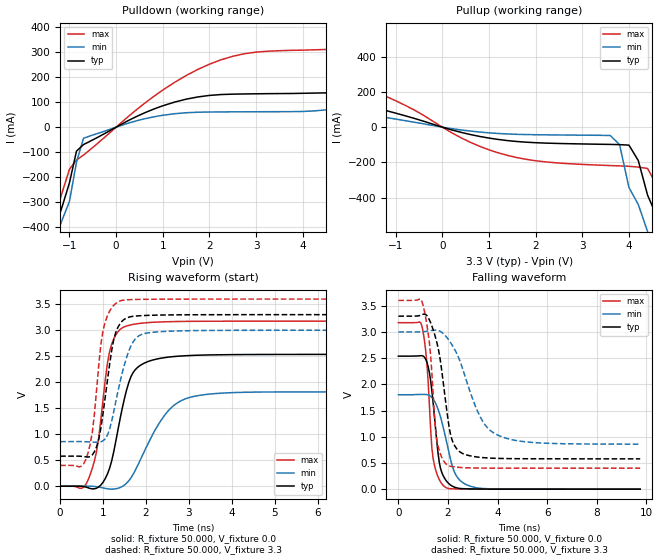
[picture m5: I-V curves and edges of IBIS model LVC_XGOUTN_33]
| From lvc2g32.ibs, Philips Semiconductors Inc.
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|   Model LVC_XGOUTN_33
[Model]   LVC_XGOUTN_33
Model_type   Output
Polarity   Non-Inverting
Vmeas =  1.5V
Cref  =  50.0pF
Rref  =  0.5k
Vref  =  0.0V
C_comp   3.30pF   2.07pF   4.36pF
[Model Spec]
| Note: The input and output voltage ratings may be exceeded if the input and
|   output current ratings are observed (please refer to the data sheet)
|   Subparameter   typ   min   max
| Timing Thresholds
Vmeas   1.5   1.5   1.5
|Ambient temperature:   25   85   -40
[Temperature Range]   35   95   -30
[Voltage Range]   3.3V   3.0V   3.6V
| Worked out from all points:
|   slope of the pulldown table from 0 to 0.495 V, typ, clamps not added: 10.4 ohm
|   slope of the pullup table from 0 to 0.495 V, typ, clamps not added: 14 ohm
|   rising waveform, R_fixture 50.000, V_fixture 0.0: 20-80 % time 409ps typ, 731ps min, 301ps max; typ from 0 V to 2.54 V
|   rising waveform, R_fixture 50.000, V_fixture 3.3: 20-80 % time 284ps typ, 377ps min, 243ps max; typ from 0.578 V to 3.3 V
|   falling waveform, R_fixture 50.000, V_fixture 0.0: 20-80 % time 340ps typ, 574ps min, 268ps max; typ from 2.54 V to 0 V
|   falling waveform, R_fixture 50.000, V_fixture 3.3: 20-80 % time 499ps typ, 1.04ns min, 318ps max; typ from 3.3 V to 0.578 V
|Process Range   nominal   slow   fast
[Pulldown]
| voltage   I(typ)   I(min)   I(max)
-5.5V     -4.541A    -4.577A    -4.501A
-1.45V    -533.3mA   -577.9mA   -483mA
-1.3V     -397.3mA   -442.4mA   -347.4mA
-1V       -221.8mA   -296.4mA   -168.2mA
-850mV    -95.82mA   -139.8mA   -131mA
-700mV    -69.66mA   -44.64mA   -111.7mA
1V        85.3mA     47.36mA    148.2mA
2.5V      131.8mA    61.07mA    283mA
5V        152.5mA    80.61mA    312.8mA
6V        202.1mA    110.9mA    399.6mA
9.25V     406.6mA    240.4mA    750.7mA
11V       533.7mA    322.1mA    955.9mA
[Pullup]
| voltage   I(typ)   I(min)   I(max)
-8V       481.6mA    323.4mA    788.9mA
-5V       330.6mA    210.3mA    573.2mA
-2.2V     163.6mA    98.17mA    292.9mA
1V        -62mA      -32.39mA   -128.5mA
3.6V      -97.95mA   -47.49mA   -218mA
3.8V      -99.13mA   -99.5mA    -219.9mA
4V        -102.1mA   -342.3mA   -221.9mA
4.2V      -189.4mA   -438.6mA   -226.5mA
4.4V      -386.3mA   -592.7mA   -234.5mA
4.8V      -702.7mA   -987.7mA   -496.5mA
5V        -905.5mA   -1.189A    -672.5mA
9.1V      -4.887A    -5.192A    -4.729A
[Ramp]
| variable   typ   min   max
dV/dt_r   1.522V/408.537ps   1.084V/731.233ps   1.905V/301.360ps
dV/dt_f   1.633V/499.135ps   1.285V/1.041ns   1.920V/318.304ps
R_load = 50.000
[Rising Waveform]
R_fixture   = 50.000
V_fixture   = 0.0
V_fixture_min = 0.0
V_fixture_max = 0.0
| time   V(typ)   V(min)   V(max)
0s        21.78pV    850.5pV    611.1pV
650ps     -29.28mV   1.614mV    118mV
850ps     -36.67mV   -8.903mV   673mV
1.15ns    339.3mV    -54.77mV   2.582V
1.5ns     1.692V     24.57mV    3.068V
1.65ns    2.106V     160.3mV    3.104V
1.9ns     2.341V     561.8mV    3.136V
2.5ns     2.481V     1.432V     3.164V
3.1ns     2.517V     1.725V     3.172V
9.75ns    2.537V     1.807V     3.176V
[Rising Waveform]
R_fixture   = 50.000
V_fixture   = 3.3
V_fixture_min = 3.0
V_fixture_max = 3.6
| time   V(typ)   V(min)   V(max)
0s        578.4mV    857.7mV    400.2mV
550ps     571mV      857.1mV    434.2mV
700ps     569mV      852.2mV    806.9mV
800ps     664.5mV    847mV      1.399V
1ns       1.404V     875.3mV    2.999V
1.25ns    2.826V     1.437V     3.481V
1.4ns     3.131V     2.021V     3.565V
1.7ns     3.268V     2.776V     3.591V
2.05ns    3.287V     2.95V      3.596V
9.75ns    3.3V       3V         3.6V
[Falling Waveform]
R_fixture   = 50.000
V_fixture   = 0.0
V_fixture_min = 0.0
V_fixture_max = 0.0
| time   V(typ)   V(min)   V(max)
0s        2.537V     1.801V     3.176V
950ps     2.545V     1.808V     3.109V
1.15ns    2.421V     1.804V     2.399V
1.35ns    1.878V     1.749V     788.3mV
1.4ns     1.652V     1.72V      591.9mV
1.65ns    511mV      1.454V     181.6mV
1.9ns     180.6mV    992.8mV    35.58mV
2.3ns     31.59mV    286.6mV    4.533mV
3ns       4.041mV    42.86mV    731.8uV
9.75ns    -19.88uV   -118.6uV   -317nV
[Falling Waveform]
R_fixture   = 50.000
V_fixture   = 3.3
V_fixture_min = 3.0
V_fixture_max = 3.6
| time   V(typ)   V(min)   V(max)
0s        3.3V       3V         3.6V
950ps     3.328V     3.002V     3.581V
1.25ns    3.229V     3.022V     2.795V
1.55ns    2.8V       3.031V     942.3mV
1.95ns    1.505V     2.896V     470.4mV
2.15ns    960.9mV    2.761V     431mV
2.4ns     745.4mV    2.541V     416.7mV
3.2ns     611.7mV    1.478V     403mV
3.9ns     588.8mV    1.057V     400.9mV
9.75ns    578.4mV    858.5mV    400.2mV
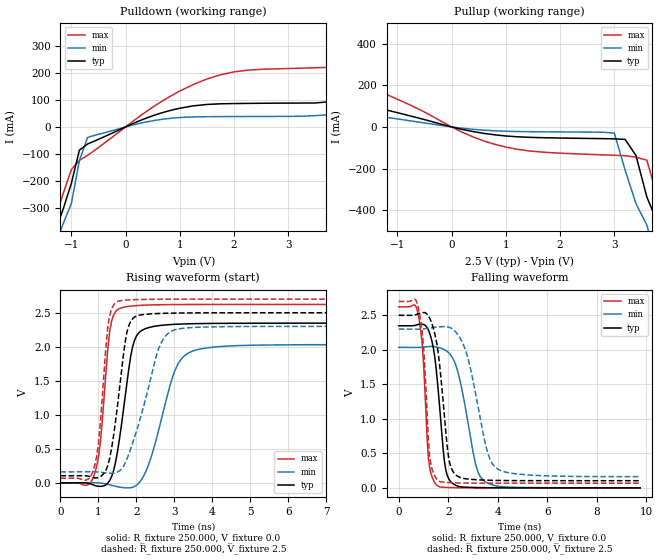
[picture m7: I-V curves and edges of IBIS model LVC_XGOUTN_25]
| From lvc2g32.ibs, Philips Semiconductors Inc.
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|   Model LVC_XGOUTN_25
[Model]   LVC_XGOUTN_25
Model_type   Output
Polarity   Non-Inverting
Vmeas =  1.25V
Cref  =  30.0pF
Rref  =  0.5k
Vref  =  0.0V
C_comp   3.37pF   2.13pF   4.36pF
[Model Spec]
| Note: The input and output voltage ratings may be exceeded if the input and
|   output current ratings are observed (please refer to the data sheet)
|   Subparameter   typ   min   max
| Timing Thresholds
Vmeas   1.25   1.15   1.35
|Ambient temperature:   25   85   -40
[Temperature Range]   30   90   -35
[Voltage Range]   2.5V   2.3V   2.7V
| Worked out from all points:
|   slope of the pulldown table from 0 to 0.375 V, typ, clamps not added: 11.7 ohm
|   slope of the pullup table from 0 to 0.375 V, typ, clamps not added: 17.6 ohm
|   rising waveform, R_fixture 250.000, V_fixture 0.0: 20-80 % time 352ps typ, 592ps min, 237ps max; typ from 0 V to 2.35 V
|   rising waveform, R_fixture 250.000, V_fixture 2.5: 20-80 % time 323ps typ, 625ps min, 224ps max; typ from 0.104 V to 2.5 V
|   falling waveform, R_fixture 250.000, V_fixture 0.0: 20-80 % time 361ps typ, 641ps min, 238ps max; typ from 2.35 V to 0 V
|   falling waveform, R_fixture 250.000, V_fixture 2.5: 20-80 % time 397ps typ, 733ps min, 251ps max; typ from 2.5 V to 0.104 V
|Process Range   nominal   slow   fast
[Pulldown]
| voltage   I(typ)   I(min)   I(max)
-5.5V     -4.533A    -4.569A    -4.49A
-1.45V    -527.2mA   -571.8mA   -476.1mA
-1.15V    -305.4mA   -359.7mA   -248.3mA
-1V       -210.6mA   -285.4mA   -158.8mA
-850mV    -86.18mA   -124.9mA   -124.2mA
-700mV    -63.39mA   -39.1mA    -105.8mA
700mV     54.21mA    29mA       98.79mA
1.75V     85.93mA    38.4mA     193.7mA
4V        101mA      50.95mA    222.9mA
5.75V     184.8mA    100.4mA    384.8mA
8.75V     371.3mA    214.2mA    702.4mA
11V       524.1mA    305.5mA    960.5mA
[Pullup]
| voltage   I(typ)   I(min)   I(max)
-8.7V     496.7mA    332.4mA    812.8mA
-4.3V     268.1mA    165.8mA    477.4mA
-2.3V     152.4mA    89.63mA    280.2mA
600mV     -31.27mA   -15.7mA    -67.93mA
1.4V      -49.67mA   -22.8mA    -114.4mA
3V        -57.33mA   -29.67mA   -136mA
3.2V      -60.09mA   -208.1mA   -138.5mA
3.4V      -137.9mA   -369.3mA   -145.7mA
3.6V      -337.3mA   -472.1mA   -160.1mA
3.8V      -461.1mA   -661.2mA   -340.5mA
4V        -655.7mA   -858.6mA   -489.1mA
8.2V      -4.75A     -4.976A    -4.541A
[Ramp]
| variable   typ   min   max
dV/dt_r   1.409V/351.702ps   1.219V/592.545ps   1.573V/237.352ps
dV/dt_f   1.438V/396.617ps   1.283V/733.339ps   1.579V/251.140ps
R_load = 250.000
[Rising Waveform]
R_fixture   = 250.000
V_fixture   = 0.0
V_fixture_min = 0.0
V_fixture_max = 0.0
| time   V(typ)   V(min)   V(max)
0s        13.04pV    425.7pV    3.82pV
900ps     -38.05mV   1.576mV    133.1mV
1.05ns    -51.64mV   -2.627mV   590mV
1.3ns     36.55mV    -28.88mV   2.238V
1.55ns    625.1mV    -62.19mV   2.561V
2ns       2.155V     -36.85mV   2.605V
2.35ns    2.285V     312mV      2.614V
3ns       2.33V      1.63V      2.62V
3.4ns     2.338V     1.917V     2.621V
9.75ns    2.348V     2.032V     2.622V
[Rising Waveform]
R_fixture   = 250.000
V_fixture   = 2.5
V_fixture_min = 2.3
V_fixture_max = 2.7
| time   V(typ)   V(min)   V(max)
0s        103.8mV    161.3mV    67.5mV
850ps     79.92mV    161.8mV    160.7mV
1ns       78.39mV    159mV      571.7mV
1.25ns    258.7mV    143.5mV    2.301V
1.5ns     1.122V     157.6mV    2.664V
1.7ns     2.053V     285mV      2.685V
1.85ns    2.372V     498.8mV    2.69V
2.6ns     2.489V     1.991V     2.698V
2.95ns    2.494V     2.236V     2.699V
9.75ns    2.5V       2.3V       2.7V
[Falling Waveform]
R_fixture   = 250.000
V_fixture   = 0.0
V_fixture_min = 0.0
V_fixture_max = 0.0
| time   V(typ)   V(min)   V(max)
0s        2.348V     2.035V     2.622V
800ps     2.368V     2.035V     2.493V
1ns       2.367V     2.038V     1.831V
1.2ns     2.286V     2.046V     433.8mV
1.55ns    1.594V     2.039V     37mV
1.85ns    379mV      2.001V     7.277mV
2ns       146.7mV    1.963V     5.024mV
3.1ns     4.934mV    348.5mV    385.6uV
3.5ns     2.703mV    88.15mV    134.6uV
9.75ns    -14.99uV   2.241uV    -620.1nV
[Falling Waveform]
R_fixture   = 250.000
V_fixture   = 2.5
V_fixture_min = 2.3
V_fixture_max = 2.7
| time   V(typ)   V(min)   V(max)
0s        2.5V       2.3V       2.7V
800ps     2.523V     2.299V     2.597V
1ns       2.54V      2.302V     2.066V
1.25ns    2.46V      2.315V     463.4mV
1.6ns     1.945V     2.331V     105.8mV
2ns       480mV      2.33V      76.78mV
2.35ns    175.9mV    2.239V     71.66mV
2.75ns    129.8mV    1.938V     69.24mV
3.9ns     108.3mV    299.8mV    67.65mV
9.75ns    103.8mV    161.8mV    67.5mV
